VERSION 5.7 ;
  NOWIREEXTENSIONATPIN ON ;
  DIVIDERCHAR "/" ;
  BUSBITCHARS "[]" ;
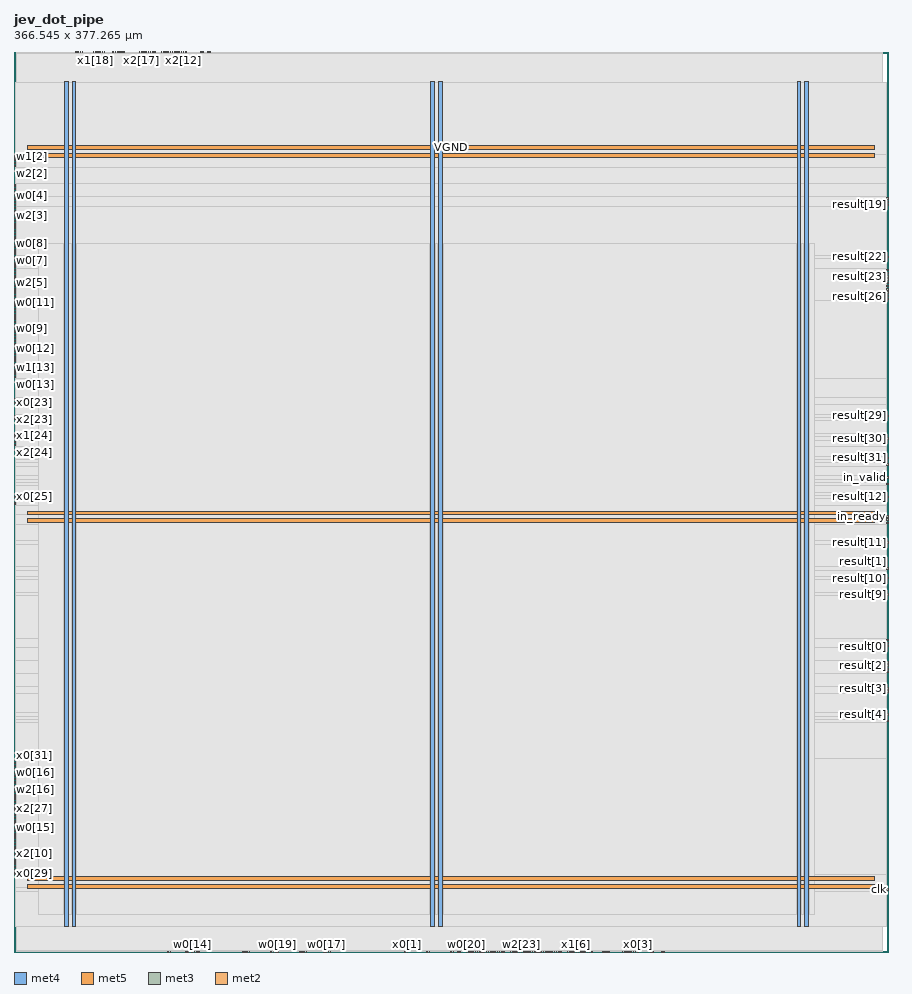
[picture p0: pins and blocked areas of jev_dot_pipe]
MACRO jev_dot_pipe
  CLASS BLOCK ;
  FOREIGN jev_dot_pipe ;
  ORIGIN 0.000 0.000 ;
  SIZE 366.545 BY 377.265 ;
  PIN VGND
    DIRECTION INOUT ;
    USE GROUND ;
    PORT
      LAYER met4 ;
        RECT 24.340 10.640 25.940 364.720 ;
    END
    PORT
      LAYER met4 ;
        RECT 177.940 10.640 179.540 364.720 ;
    END
    PORT
      LAYER met4 ;
        RECT 331.540 10.640 333.140 364.720 ;
    END
    PORT
      LAYER met5 ;
        RECT 5.520 30.030 360.640 31.630 ;
    END
    PORT
      LAYER met5 ;
        RECT 5.520 183.210 360.640 184.810 ;
    END
    PORT
      LAYER met5 ;
        RECT 5.520 336.390 360.640 337.990 ;
    END
  END VGND
  PIN VPWR
    DIRECTION INOUT ;
    USE POWER ;
    PORT
      LAYER met4 ;
        RECT 21.040 10.640 22.640 364.720 ;
    END
    PORT
      LAYER met4 ;
        RECT 174.640 10.640 176.240 364.720 ;
    END
    PORT
      LAYER met4 ;
        RECT 328.240 10.640 329.840 364.720 ;
    END
    PORT
      LAYER met5 ;
        RECT 5.520 26.730 360.640 28.330 ;
    END
    PORT
      LAYER met5 ;
        RECT 5.520 179.910 360.640 181.510 ;
    END
    PORT
      LAYER met5 ;
        RECT 5.520 333.090 360.640 334.690 ;
    END
  END VPWR
  PIN clk
    DIRECTION INPUT ;
    USE SIGNAL ;
    ANTENNAGATEAREA 0.852000 ;
    PORT
      LAYER met3 ;
        RECT 365.945 25.880 366.545 26.480 ;
    END
  END clk
  PIN in_ready
    DIRECTION OUTPUT ;
    USE SIGNAL ;
    ANTENNADIFFAREA 0.383400 ;
    PORT
      LAYER met3 ;
        RECT 365.945 182.280 366.545 182.880 ;
    END
  END in_ready
  PIN in_valid
    DIRECTION INPUT ;
    USE SIGNAL ;
    ANTENNAGATEAREA 0.196500 ;
    PORT
      LAYER met3 ;
        RECT 365.945 198.600 366.545 199.200 ;
    END
  END in_valid
  PIN out_ready
    DIRECTION INPUT ;
    USE SIGNAL ;
    ANTENNAGATEAREA 0.196500 ;
    PORT
      LAYER met3 ;
        RECT 365.945 180.920 366.545 181.520 ;
    END
  END out_ready
  PIN out_valid
    DIRECTION OUTPUT ;
    USE SIGNAL ;
    ANTENNADIFFAREA 0.383400 ;
    PORT
      LAYER met3 ;
        RECT 365.945 179.560 366.545 180.160 ;
    END
  END out_valid
  PIN result[0]
    DIRECTION OUTPUT ;
    USE SIGNAL ;
    ANTENNADIFFAREA 0.383400 ;
    PORT
      LAYER met3 ;
        RECT 365.945 127.880 366.545 128.480 ;
    END
  END result[0]
  PIN result[10]
    DIRECTION OUTPUT ;
    USE SIGNAL ;
    ANTENNADIFFAREA 0.383400 ;
    PORT
      LAYER met3 ;
        RECT 365.945 156.440 366.545 157.040 ;
    END
  END result[10]
  PIN result[11]
    DIRECTION OUTPUT ;
    USE SIGNAL ;
    ANTENNADIFFAREA 0.383400 ;
    PORT
      LAYER met3 ;
        RECT 365.945 171.400 366.545 172.000 ;
    END
  END result[11]
  PIN result[12]
    DIRECTION OUTPUT ;
    USE SIGNAL ;
    ANTENNADIFFAREA 0.383400 ;
    PORT
      LAYER met3 ;
        RECT 365.945 190.440 366.545 191.040 ;
    END
  END result[12]
  PIN result[13]
    DIRECTION OUTPUT ;
    USE SIGNAL ;
    ANTENNADIFFAREA 0.383400 ;
    PORT
      LAYER met3 ;
        RECT 365.945 195.880 366.545 196.480 ;
    END
  END result[13]
  PIN result[14]
    DIRECTION OUTPUT ;
    USE SIGNAL ;
    ANTENNADIFFAREA 0.383400 ;
    PORT
      LAYER met3 ;
        RECT 365.945 281.560 366.545 282.160 ;
    END
  END result[14]
  PIN result[15]
    DIRECTION OUTPUT ;
    USE SIGNAL ;
    ANTENNADIFFAREA 0.383400 ;
    PORT
      LAYER met3 ;
        RECT 365.945 280.200 366.545 280.800 ;
    END
  END result[15]
  PIN result[16]
    DIRECTION OUTPUT ;
    USE SIGNAL ;
    ANTENNADIFFAREA 0.383400 ;
    PORT
      LAYER met3 ;
        RECT 365.945 274.760 366.545 275.360 ;
    END
  END result[16]
  PIN result[17]
    DIRECTION OUTPUT ;
    USE SIGNAL ;
    ANTENNADIFFAREA 0.383400 ;
    PORT
      LAYER met3 ;
        RECT 365.945 285.640 366.545 286.240 ;
    END
  END result[17]
  PIN result[18]
    DIRECTION OUTPUT ;
    USE SIGNAL ;
    ANTENNADIFFAREA 0.383400 ;
    PORT
      LAYER met3 ;
        RECT 365.945 284.280 366.545 284.880 ;
    END
  END result[18]
  PIN result[19]
    DIRECTION OUTPUT ;
    USE SIGNAL ;
    ANTENNADIFFAREA 0.383400 ;
    PORT
      LAYER met3 ;
        RECT 365.945 312.840 366.545 313.440 ;
    END
  END result[19]
  PIN result[1]
    DIRECTION OUTPUT ;
    USE SIGNAL ;
    ANTENNADIFFAREA 0.383400 ;
    PORT
      LAYER met3 ;
        RECT 365.945 160.520 366.545 161.120 ;
    END
  END result[1]
  PIN result[20]
    DIRECTION OUTPUT ;
    USE SIGNAL ;
    ANTENNADIFFAREA 0.383400 ;
    PORT
      LAYER met3 ;
        RECT 365.945 314.200 366.545 314.800 ;
    END
  END result[20]
  PIN result[21]
    DIRECTION OUTPUT ;
    USE SIGNAL ;
    ANTENNADIFFAREA 0.383400 ;
    PORT
      LAYER met3 ;
        RECT 365.945 315.560 366.545 316.160 ;
    END
  END result[21]
  PIN result[22]
    DIRECTION OUTPUT ;
    USE SIGNAL ;
    ANTENNADIFFAREA 0.383400 ;
    PORT
      LAYER met3 ;
        RECT 365.945 291.080 366.545 291.680 ;
    END
  END result[22]
  PIN result[23]
    DIRECTION OUTPUT ;
    USE SIGNAL ;
    ANTENNADIFFAREA 0.383400 ;
    PORT
      LAYER met3 ;
        RECT 365.945 282.920 366.545 283.520 ;
    END
  END result[23]
  PIN result[24]
    DIRECTION OUTPUT ;
    USE SIGNAL ;
    ANTENNADIFFAREA 0.383400 ;
    PORT
      LAYER met3 ;
        RECT 365.945 276.120 366.545 276.720 ;
    END
  END result[24]
  PIN result[25]
    DIRECTION OUTPUT ;
    USE SIGNAL ;
    ANTENNADIFFAREA 0.383400 ;
    PORT
      LAYER met3 ;
        RECT 365.945 278.840 366.545 279.440 ;
    END
  END result[25]
  PIN result[26]
    DIRECTION OUTPUT ;
    USE SIGNAL ;
    ANTENNADIFFAREA 0.383400 ;
    PORT
      LAYER met3 ;
        RECT 365.945 277.480 366.545 278.080 ;
    END
  END result[26]
  PIN result[27]
    DIRECTION OUTPUT ;
    USE SIGNAL ;
    ANTENNADIFFAREA 0.383400 ;
    PORT
      LAYER met3 ;
        RECT 365.945 273.400 366.545 274.000 ;
    END
  END result[27]
  PIN result[28]
    DIRECTION OUTPUT ;
    USE SIGNAL ;
    ANTENNADIFFAREA 0.383400 ;
    PORT
      LAYER met3 ;
        RECT 365.945 206.760 366.545 207.360 ;
    END
  END result[28]
  PIN result[29]
    DIRECTION OUTPUT ;
    USE SIGNAL ;
    ANTENNADIFFAREA 0.383400 ;
    PORT
      LAYER met3 ;
        RECT 365.945 224.440 366.545 225.040 ;
    END
  END result[29]
  PIN result[2]
    DIRECTION OUTPUT ;
    USE SIGNAL ;
    ANTENNADIFFAREA 0.383400 ;
    PORT
      LAYER met3 ;
        RECT 365.945 119.720 366.545 120.320 ;
    END
  END result[2]
  PIN result[30]
    DIRECTION OUTPUT ;
    USE SIGNAL ;
    ANTENNADIFFAREA 0.383400 ;
    PORT
      LAYER met3 ;
        RECT 365.945 214.920 366.545 215.520 ;
    END
  END result[30]
  PIN result[31]
    DIRECTION OUTPUT ;
    USE SIGNAL ;
    ANTENNADIFFAREA 0.383400 ;
    PORT
      LAYER met3 ;
        RECT 365.945 204.040 366.545 204.640 ;
    END
  END result[31]
  PIN result[3]
    DIRECTION OUTPUT ;
    USE SIGNAL ;
    ANTENNADIFFAREA 0.383400 ;
    PORT
      LAYER met3 ;
        RECT 365.945 110.200 366.545 110.800 ;
    END
  END result[3]
  PIN result[4]
    DIRECTION OUTPUT ;
    USE SIGNAL ;
    ANTENNADIFFAREA 0.383400 ;
    PORT
      LAYER met3 ;
        RECT 365.945 99.320 366.545 99.920 ;
    END
  END result[4]
  PIN result[5]
    DIRECTION OUTPUT ;
    USE SIGNAL ;
    ANTENNADIFFAREA 0.383400 ;
    PORT
      LAYER met3 ;
        RECT 365.945 96.600 366.545 97.200 ;
    END
  END result[5]
  PIN result[6]
    DIRECTION OUTPUT ;
    USE SIGNAL ;
    ANTENNADIFFAREA 0.383400 ;
    PORT
      LAYER met3 ;
        RECT 365.945 108.840 366.545 109.440 ;
    END
  END result[6]
  PIN result[7]
    DIRECTION OUTPUT ;
    USE SIGNAL ;
    ANTENNADIFFAREA 0.383400 ;
    PORT
      LAYER met3 ;
        RECT 365.945 121.080 366.545 121.680 ;
    END
  END result[7]
  PIN result[8]
    DIRECTION OUTPUT ;
    USE SIGNAL ;
    ANTENNADIFFAREA 0.383400 ;
    PORT
      LAYER met3 ;
        RECT 365.945 130.600 366.545 131.200 ;
    END
  END result[8]
  PIN result[9]
    DIRECTION OUTPUT ;
    USE SIGNAL ;
    ANTENNADIFFAREA 0.383400 ;
    PORT
      LAYER met3 ;
        RECT 365.945 149.640 366.545 150.240 ;
    END
  END result[9]
  PIN rst
    DIRECTION INPUT ;
    USE SIGNAL ;
    ANTENNAGATEAREA 0.213000 ;
    PORT
      LAYER met3 ;
        RECT 365.945 129.240 366.545 129.840 ;
    END
  END rst
  PIN w0[0]
    DIRECTION INPUT ;
    USE SIGNAL ;
    ANTENNAGATEAREA 0.196500 ;
    PORT
      LAYER met2 ;
        RECT 37.810 376.985 38.090 377.265 ;
    END
  END w0[0]
  PIN w0[10]
    DIRECTION INPUT ;
    USE SIGNAL ;
    ANTENNAGATEAREA 0.196500 ;
    PORT
      LAYER met3 ;
        RECT 0.000 281.560 0.600 282.160 ;
    END
  END w0[10]
  PIN w0[11]
    DIRECTION INPUT ;
    USE SIGNAL ;
    ANTENNAGATEAREA 0.196500 ;
    PORT
      LAYER met3 ;
        RECT 0.000 272.040 0.600 272.640 ;
    END
  END w0[11]
  PIN w0[12]
    DIRECTION INPUT ;
    USE SIGNAL ;
    ANTENNAGATEAREA 0.196500 ;
    PORT
      LAYER met3 ;
        RECT 0.000 255.720 0.600 256.320 ;
    END
  END w0[12]
  PIN w0[13]
    DIRECTION INPUT ;
    USE SIGNAL ;
    ANTENNAGATEAREA 0.196500 ;
    PORT
      LAYER met3 ;
        RECT 0.000 240.760 0.600 241.360 ;
    END
  END w0[13]
  PIN w0[14]
    DIRECTION INPUT ;
    USE SIGNAL ;
    ANTENNAGATEAREA 0.196500 ;
    PORT
      LAYER met2 ;
        RECT 74.610 0.000 74.890 0.280 ;
    END
  END w0[14]
  PIN w0[15]
    DIRECTION INPUT ;
    USE SIGNAL ;
    ANTENNAGATEAREA 0.196500 ;
    PORT
      LAYER met3 ;
        RECT 0.000 51.720 0.600 52.320 ;
    END
  END w0[15]
  PIN w0[16]
    DIRECTION INPUT ;
    USE SIGNAL ;
    ANTENNAGATEAREA 0.196500 ;
    PORT
      LAYER met3 ;
        RECT 0.000 74.840 0.600 75.440 ;
    END
  END w0[16]
  PIN w0[17]
    DIRECTION INPUT ;
    USE SIGNAL ;
    ANTENNAGATEAREA 0.196500 ;
    PORT
      LAYER met2 ;
        RECT 130.730 0.000 131.010 0.280 ;
    END
  END w0[17]
  PIN w0[18]
    DIRECTION INPUT ;
    USE SIGNAL ;
    ANTENNAGATEAREA 0.196500 ;
    PORT
      LAYER met2 ;
        RECT 122.450 0.000 122.730 0.280 ;
    END
  END w0[18]
  PIN w0[19]
    DIRECTION INPUT ;
    USE SIGNAL ;
    ANTENNAGATEAREA 0.196500 ;
    PORT
      LAYER met2 ;
        RECT 110.490 0.000 110.770 0.280 ;
    END
  END w0[19]
  PIN w0[1]
    DIRECTION INPUT ;
    USE SIGNAL ;
    ANTENNAGATEAREA 0.196500 ;
    PORT
      LAYER met2 ;
        RECT 26.770 376.985 27.050 377.265 ;
    END
  END w0[1]
  PIN w0[20]
    DIRECTION INPUT ;
    USE SIGNAL ;
    ANTENNAGATEAREA 0.196500 ;
    PORT
      LAYER met2 ;
        RECT 189.610 0.000 189.890 0.280 ;
    END
  END w0[20]
  PIN w0[21]
    DIRECTION INPUT ;
    USE SIGNAL ;
    ANTENNAGATEAREA 0.196500 ;
    PORT
      LAYER met2 ;
        RECT 201.570 0.000 201.850 0.280 ;
    END
  END w0[21]
  PIN w0[22]
    DIRECTION INPUT ;
    USE SIGNAL ;
    ANTENNAGATEAREA 0.196500 ;
    PORT
      LAYER met3 ;
        RECT 365.945 117.000 366.545 117.600 ;
    END
  END w0[22]
  PIN w0[23]
    DIRECTION INPUT ;
    USE SIGNAL ;
    ANTENNAGATEAREA 0.196500 ;
    PORT
      LAYER met2 ;
        RECT 218.130 0.000 218.410 0.280 ;
    END
  END w0[23]
  PIN w0[24]
    DIRECTION INPUT ;
    USE SIGNAL ;
    ANTENNAGATEAREA 0.196500 ;
    PORT
      LAYER met2 ;
        RECT 208.010 0.000 208.290 0.280 ;
    END
  END w0[24]
  PIN w0[25]
    DIRECTION INPUT ;
    USE SIGNAL ;
    ANTENNAGATEAREA 0.196500 ;
    PORT
      LAYER met2 ;
        RECT 225.490 0.000 225.770 0.280 ;
    END
  END w0[25]
  PIN w0[26]
    DIRECTION INPUT ;
    USE SIGNAL ;
    ANTENNAGATEAREA 0.196500 ;
    PORT
      LAYER met2 ;
        RECT 229.170 0.000 229.450 0.280 ;
    END
  END w0[26]
  PIN w0[27]
    DIRECTION INPUT ;
    USE SIGNAL ;
    ANTENNAGATEAREA 0.196500 ;
    PORT
      LAYER met2 ;
        RECT 242.050 0.000 242.330 0.280 ;
    END
  END w0[27]
  PIN w0[28]
    DIRECTION INPUT ;
    USE SIGNAL ;
    ANTENNAGATEAREA 0.196500 ;
    PORT
      LAYER met2 ;
        RECT 234.690 0.000 234.970 0.280 ;
    END
  END w0[28]
  PIN w0[29]
    DIRECTION INPUT ;
    USE SIGNAL ;
    ANTENNAGATEAREA 0.196500 ;
    PORT
      LAYER met2 ;
        RECT 216.290 0.000 216.570 0.280 ;
    END
  END w0[29]
  PIN w0[2]
    DIRECTION INPUT ;
    USE SIGNAL ;
    ANTENNAGATEAREA 0.196500 ;
    PORT
      LAYER met3 ;
        RECT 0.000 331.880 0.600 332.480 ;
    END
  END w0[2]
  PIN w0[30]
    DIRECTION INPUT ;
    USE SIGNAL ;
    ANTENNAGATEAREA 0.196500 ;
    PORT
      LAYER met2 ;
        RECT 196.050 0.000 196.330 0.280 ;
    END
  END w0[30]
  PIN w0[31]
    DIRECTION INPUT ;
    USE SIGNAL ;
    ANTENNAGATEAREA 0.196500 ;
    PORT
      LAYER met2 ;
        RECT 223.650 0.000 223.930 0.280 ;
    END
  END w0[31]
  PIN w0[3]
    DIRECTION INPUT ;
    USE SIGNAL ;
    ANTENNAGATEAREA 0.196500 ;
    PORT
      LAYER met3 ;
        RECT 0.000 315.560 0.600 316.160 ;
    END
  END w0[3]
  PIN w0[4]
    DIRECTION INPUT ;
    USE SIGNAL ;
    ANTENNAGATEAREA 0.196500 ;
    PORT
      LAYER met3 ;
        RECT 0.000 316.920 0.600 317.520 ;
    END
  END w0[4]
  PIN w0[5]
    DIRECTION INPUT ;
    USE SIGNAL ;
    ANTENNAGATEAREA 0.196500 ;
    PORT
      LAYER met3 ;
        RECT 0.000 273.400 0.600 274.000 ;
    END
  END w0[5]
  PIN w0[6]
    DIRECTION INPUT ;
    USE SIGNAL ;
    ANTENNAGATEAREA 0.196500 ;
    PORT
      LAYER met3 ;
        RECT 0.000 267.960 0.600 268.560 ;
    END
  END w0[6]
  PIN w0[7]
    DIRECTION INPUT ;
    USE SIGNAL ;
    ANTENNAGATEAREA 0.196500 ;
    PORT
      LAYER met3 ;
        RECT 0.000 289.720 0.600 290.320 ;
    END
  END w0[7]
  PIN w0[8]
    DIRECTION INPUT ;
    USE SIGNAL ;
    ANTENNAGATEAREA 0.196500 ;
    PORT
      LAYER met3 ;
        RECT 0.000 293.800 0.600 294.400 ;
    END
  END w0[8]
  PIN w0[9]
    DIRECTION INPUT ;
    USE SIGNAL ;
    ANTENNAGATEAREA 0.196500 ;
    PORT
      LAYER met3 ;
        RECT 0.000 261.160 0.600 261.760 ;
    END
  END w0[9]
  PIN w1[0]
    DIRECTION INPUT ;
    USE SIGNAL ;
    ANTENNAGATEAREA 0.196500 ;
    PORT
      LAYER met2 ;
        RECT 36.890 376.985 37.170 377.265 ;
    END
  END w1[0]
  PIN w1[10]
    DIRECTION INPUT ;
    USE SIGNAL ;
    ANTENNAGATEAREA 0.196500 ;
    PORT
      LAYER met3 ;
        RECT 0.000 285.640 0.600 286.240 ;
    END
  END w1[10]
  PIN w1[11]
    DIRECTION INPUT ;
    USE SIGNAL ;
    ANTENNAGATEAREA 0.196500 ;
    PORT
      LAYER met3 ;
        RECT 0.000 274.760 0.600 275.360 ;
    END
  END w1[11]
  PIN w1[12]
    DIRECTION INPUT ;
    USE SIGNAL ;
    ANTENNAGATEAREA 0.196500 ;
    PORT
      LAYER met3 ;
        RECT 0.000 254.360 0.600 254.960 ;
    END
  END w1[12]
  PIN w1[13]
    DIRECTION INPUT ;
    USE SIGNAL ;
    ANTENNAGATEAREA 0.196500 ;
    PORT
      LAYER met3 ;
        RECT 0.000 244.840 0.600 245.440 ;
    END
  END w1[13]
  PIN w1[14]
    DIRECTION INPUT ;
    USE SIGNAL ;
    ANTENNAGATEAREA 0.196500 ;
    PORT
      LAYER met2 ;
        RECT 75.530 0.000 75.810 0.280 ;
    END
  END w1[14]
  PIN w1[15]
    DIRECTION INPUT ;
    USE SIGNAL ;
    ANTENNAGATEAREA 0.196500 ;
    PORT
      LAYER met3 ;
        RECT 0.000 53.080 0.600 53.680 ;
    END
  END w1[15]
  PIN w1[16]
    DIRECTION INPUT ;
    USE SIGNAL ;
    ANTENNAGATEAREA 0.196500 ;
    PORT
      LAYER met3 ;
        RECT 0.000 72.120 0.600 72.720 ;
    END
  END w1[16]
  PIN w1[17]
    DIRECTION INPUT ;
    USE SIGNAL ;
    ANTENNAGATEAREA 0.196500 ;
    PORT
      LAYER met2 ;
        RECT 129.810 0.000 130.090 0.280 ;
    END
  END w1[17]
  PIN w1[18]
    DIRECTION INPUT ;
    USE SIGNAL ;
    ANTENNAGATEAREA 0.196500 ;
    PORT
      LAYER met2 ;
        RECT 121.530 0.000 121.810 0.280 ;
    END
  END w1[18]
  PIN w1[19]
    DIRECTION INPUT ;
    USE SIGNAL ;
    ANTENNAGATEAREA 0.196500 ;
    PORT
      LAYER met2 ;
        RECT 109.570 0.000 109.850 0.280 ;
    END
  END w1[19]
  PIN w1[1]
    DIRECTION INPUT ;
    USE SIGNAL ;
    ANTENNAGATEAREA 0.196500 ;
    PORT
      LAYER met2 ;
        RECT 25.850 376.985 26.130 377.265 ;
    END
  END w1[1]
  PIN w1[20]
    DIRECTION INPUT ;
    USE SIGNAL ;
    ANTENNAGATEAREA 0.196500 ;
    PORT
      LAYER met2 ;
        RECT 190.530 0.000 190.810 0.280 ;
    END
  END w1[20]
  PIN w1[21]
    DIRECTION INPUT ;
    USE SIGNAL ;
    ANTENNAGATEAREA 0.196500 ;
    PORT
      LAYER met2 ;
        RECT 200.650 0.000 200.930 0.280 ;
    END
  END w1[21]
  PIN w1[22]
    DIRECTION INPUT ;
    USE SIGNAL ;
    ANTENNAGATEAREA 0.196500 ;
    PORT
      LAYER met3 ;
        RECT 365.945 118.360 366.545 118.960 ;
    END
  END w1[22]
  PIN w1[23]
    DIRECTION INPUT ;
    USE SIGNAL ;
    ANTENNAGATEAREA 0.196500 ;
    PORT
      LAYER met2 ;
        RECT 217.210 0.000 217.490 0.280 ;
    END
  END w1[23]
  PIN w1[24]
    DIRECTION INPUT ;
    USE SIGNAL ;
    ANTENNAGATEAREA 0.196500 ;
    PORT
      LAYER met2 ;
        RECT 210.770 0.000 211.050 0.280 ;
    END
  END w1[24]
  PIN w1[25]
    DIRECTION INPUT ;
    USE SIGNAL ;
    ANTENNAGATEAREA 0.196500 ;
    PORT
      LAYER met2 ;
        RECT 224.570 0.000 224.850 0.280 ;
    END
  END w1[25]
  PIN w1[26]
    DIRECTION INPUT ;
    USE SIGNAL ;
    ANTENNAGATEAREA 0.196500 ;
    PORT
      LAYER met2 ;
        RECT 228.250 0.000 228.530 0.280 ;
    END
  END w1[26]
  PIN w1[27]
    DIRECTION INPUT ;
    USE SIGNAL ;
    ANTENNAGATEAREA 0.196500 ;
    PORT
      LAYER met2 ;
        RECT 241.130 0.000 241.410 0.280 ;
    END
  END w1[27]
  PIN w1[28]
    DIRECTION INPUT ;
    USE SIGNAL ;
    ANTENNAGATEAREA 0.196500 ;
    PORT
      LAYER met2 ;
        RECT 233.770 0.000 234.050 0.280 ;
    END
  END w1[28]
  PIN w1[29]
    DIRECTION INPUT ;
    USE SIGNAL ;
    ANTENNAGATEAREA 0.196500 ;
    PORT
      LAYER met2 ;
        RECT 214.450 0.000 214.730 0.280 ;
    END
  END w1[29]
  PIN w1[2]
    DIRECTION INPUT ;
    USE SIGNAL ;
    ANTENNAGATEAREA 0.196500 ;
    PORT
      LAYER met3 ;
        RECT 0.000 333.240 0.600 333.840 ;
    END
  END w1[2]
  PIN w1[30]
    DIRECTION INPUT ;
    USE SIGNAL ;
    ANTENNAGATEAREA 0.196500 ;
    PORT
      LAYER met2 ;
        RECT 195.130 0.000 195.410 0.280 ;
    END
  END w1[30]
  PIN w1[31]
    DIRECTION INPUT ;
    USE SIGNAL ;
    ANTENNAGATEAREA 0.196500 ;
    PORT
      LAYER met2 ;
        RECT 219.050 0.000 219.330 0.280 ;
    END
  END w1[31]
  PIN w1[3]
    DIRECTION INPUT ;
    USE SIGNAL ;
    ANTENNAGATEAREA 0.196500 ;
    PORT
      LAYER met3 ;
        RECT 0.000 312.840 0.600 313.440 ;
    END
  END w1[3]
  PIN w1[4]
    DIRECTION INPUT ;
    USE SIGNAL ;
    ANTENNAGATEAREA 0.196500 ;
    PORT
      LAYER met3 ;
        RECT 0.000 318.280 0.600 318.880 ;
    END
  END w1[4]
  PIN w1[5]
    DIRECTION INPUT ;
    USE SIGNAL ;
    ANTENNAGATEAREA 0.196500 ;
    PORT
      LAYER met3 ;
        RECT 0.000 276.120 0.600 276.720 ;
    END
  END w1[5]
  PIN w1[6]
    DIRECTION INPUT ;
    USE SIGNAL ;
    ANTENNAGATEAREA 0.196500 ;
    PORT
      LAYER met3 ;
        RECT 0.000 269.320 0.600 269.920 ;
    END
  END w1[6]
  PIN w1[7]
    DIRECTION INPUT ;
    USE SIGNAL ;
    ANTENNAGATEAREA 0.196500 ;
    PORT
      LAYER met3 ;
        RECT 0.000 292.440 0.600 293.040 ;
    END
  END w1[7]
  PIN w1[8]
    DIRECTION INPUT ;
    USE SIGNAL ;
    ANTENNAGATEAREA 0.196500 ;
    PORT
      LAYER met3 ;
        RECT 0.000 291.080 0.600 291.680 ;
    END
  END w1[8]
  PIN w1[9]
    DIRECTION INPUT ;
    USE SIGNAL ;
    ANTENNAGATEAREA 0.196500 ;
    PORT
      LAYER met3 ;
        RECT 0.000 262.520 0.600 263.120 ;
    END
  END w1[9]
  PIN w2[0]
    DIRECTION INPUT ;
    USE SIGNAL ;
    ANTENNAGATEAREA 0.196500 ;
    PORT
      LAYER met2 ;
        RECT 41.490 376.985 41.770 377.265 ;
    END
  END w2[0]
  PIN w2[10]
    DIRECTION INPUT ;
    USE SIGNAL ;
    ANTENNAGATEAREA 0.196500 ;
    PORT
      LAYER met3 ;
        RECT 0.000 270.680 0.600 271.280 ;
    END
  END w2[10]
  PIN w2[11]
    DIRECTION INPUT ;
    USE SIGNAL ;
    ANTENNAGATEAREA 0.196500 ;
    PORT
      LAYER met3 ;
        RECT 0.000 259.800 0.600 260.400 ;
    END
  END w2[11]
  PIN w2[12]
    DIRECTION INPUT ;
    USE SIGNAL ;
    ANTENNAGATEAREA 0.196500 ;
    PORT
      LAYER met3 ;
        RECT 0.000 251.640 0.600 252.240 ;
    END
  END w2[12]
  PIN w2[13]
    DIRECTION INPUT ;
    USE SIGNAL ;
    ANTENNAGATEAREA 0.196500 ;
    PORT
      LAYER met3 ;
        RECT 0.000 242.120 0.600 242.720 ;
    END
  END w2[13]
  PIN w2[14]
    DIRECTION INPUT ;
    USE SIGNAL ;
    ANTENNAGATEAREA 0.196500 ;
    PORT
      LAYER met3 ;
        RECT 0.000 63.960 0.600 64.560 ;
    END
  END w2[14]
  PIN w2[15]
    DIRECTION INPUT ;
    USE SIGNAL ;
    ANTENNAGATEAREA 0.196500 ;
    PORT
      LAYER met3 ;
        RECT 0.000 62.600 0.600 63.200 ;
    END
  END w2[15]
  PIN w2[16]
    DIRECTION INPUT ;
    USE SIGNAL ;
    ANTENNAGATEAREA 0.196500 ;
    PORT
      LAYER met3 ;
        RECT 0.000 70.760 0.600 71.360 ;
    END
  END w2[16]
  PIN w2[17]
    DIRECTION INPUT ;
    USE SIGNAL ;
    ANTENNAGATEAREA 0.196500 ;
    PORT
      LAYER met2 ;
        RECT 132.570 0.000 132.850 0.280 ;
    END
  END w2[17]
  PIN w2[18]
    DIRECTION INPUT ;
    USE SIGNAL ;
    ANTENNAGATEAREA 0.196500 ;
    PORT
      LAYER met2 ;
        RECT 120.610 0.000 120.890 0.280 ;
    END
  END w2[18]
  PIN w2[19]
    DIRECTION INPUT ;
    USE SIGNAL ;
    ANTENNAGATEAREA 0.196500 ;
    PORT
      LAYER met2 ;
        RECT 108.650 0.000 108.930 0.280 ;
    END
  END w2[19]
  PIN w2[1]
    DIRECTION INPUT ;
    USE SIGNAL ;
    ANTENNAGATEAREA 0.196500 ;
    PORT
      LAYER met2 ;
        RECT 28.610 376.985 28.890 377.265 ;
    END
  END w2[1]
  PIN w2[20]
    DIRECTION INPUT ;
    USE SIGNAL ;
    ANTENNAGATEAREA 0.196500 ;
    PORT
      LAYER met2 ;
        RECT 192.370 0.000 192.650 0.280 ;
    END
  END w2[20]
  PIN w2[21]
    DIRECTION INPUT ;
    USE SIGNAL ;
    ANTENNAGATEAREA 0.196500 ;
    PORT
      LAYER met2 ;
        RECT 198.810 0.000 199.090 0.280 ;
    END
  END w2[21]
  PIN w2[22]
    DIRECTION INPUT ;
    USE SIGNAL ;
    ANTENNAGATEAREA 0.196500 ;
    PORT
      LAYER met2 ;
        RECT 197.890 0.000 198.170 0.280 ;
    END
  END w2[22]
  PIN w2[23]
    DIRECTION INPUT ;
    USE SIGNAL ;
    ANTENNAGATEAREA 0.196500 ;
    PORT
      LAYER met2 ;
        RECT 212.610 0.000 212.890 0.280 ;
    END
  END w2[23]
  PIN w2[24]
    DIRECTION INPUT ;
    USE SIGNAL ;
    ANTENNAGATEAREA 0.196500 ;
    PORT
      LAYER met2 ;
        RECT 209.850 0.000 210.130 0.280 ;
    END
  END w2[24]
  PIN w2[25]
    DIRECTION INPUT ;
    USE SIGNAL ;
    ANTENNAGATEAREA 0.196500 ;
    PORT
      LAYER met2 ;
        RECT 219.970 0.000 220.250 0.280 ;
    END
  END w2[25]
  PIN w2[26]
    DIRECTION INPUT ;
    USE SIGNAL ;
    ANTENNAGATEAREA 0.196500 ;
    PORT
      LAYER met2 ;
        RECT 227.330 0.000 227.610 0.280 ;
    END
  END w2[26]
  PIN w2[27]
    DIRECTION INPUT ;
    USE SIGNAL ;
    ANTENNAGATEAREA 0.196500 ;
    PORT
      LAYER met2 ;
        RECT 240.210 0.000 240.490 0.280 ;
    END
  END w2[27]
  PIN w2[28]
    DIRECTION INPUT ;
    USE SIGNAL ;
    ANTENNAGATEAREA 0.196500 ;
    PORT
      LAYER met2 ;
        RECT 232.850 0.000 233.130 0.280 ;
    END
  END w2[28]
  PIN w2[29]
    DIRECTION INPUT ;
    USE SIGNAL ;
    ANTENNAGATEAREA 0.196500 ;
    PORT
      LAYER met2 ;
        RECT 213.530 0.000 213.810 0.280 ;
    END
  END w2[29]
  PIN w2[2]
    DIRECTION INPUT ;
    USE SIGNAL ;
    ANTENNAGATEAREA 0.196500 ;
    PORT
      LAYER met3 ;
        RECT 0.000 329.160 0.600 329.760 ;
    END
  END w2[2]
  PIN w2[30]
    DIRECTION INPUT ;
    USE SIGNAL ;
    ANTENNAGATEAREA 0.196500 ;
    PORT
      LAYER met2 ;
        RECT 194.210 0.000 194.490 0.280 ;
    END
  END w2[30]
  PIN w2[31]
    DIRECTION INPUT ;
    USE SIGNAL ;
    ANTENNAGATEAREA 0.196500 ;
    PORT
      LAYER met2 ;
        RECT 220.890 0.000 221.170 0.280 ;
    END
  END w2[31]
  PIN w2[3]
    DIRECTION INPUT ;
    USE SIGNAL ;
    ANTENNAGATEAREA 0.196500 ;
    PORT
      LAYER met3 ;
        RECT 0.000 311.480 0.600 312.080 ;
    END
  END w2[3]
  PIN w2[4]
    DIRECTION INPUT ;
    USE SIGNAL ;
    ANTENNAGATEAREA 0.196500 ;
    PORT
      LAYER met3 ;
        RECT 0.000 321.000 0.600 321.600 ;
    END
  END w2[4]
  PIN w2[5]
    DIRECTION INPUT ;
    USE SIGNAL ;
    ANTENNAGATEAREA 0.196500 ;
    PORT
      LAYER met3 ;
        RECT 0.000 277.480 0.600 278.080 ;
    END
  END w2[5]
  PIN w2[6]
    DIRECTION INPUT ;
    USE SIGNAL ;
    ANTENNAGATEAREA 0.196500 ;
    PORT
      LAYER met3 ;
        RECT 0.000 257.080 0.600 257.680 ;
    END
  END w2[6]
  PIN w2[7]
    DIRECTION INPUT ;
    USE SIGNAL ;
    ANTENNAGATEAREA 0.196500 ;
    PORT
      LAYER met3 ;
        RECT 0.000 287.000 0.600 287.600 ;
    END
  END w2[7]
  PIN w2[8]
    DIRECTION INPUT ;
    USE SIGNAL ;
    ANTENNAGATEAREA 0.196500 ;
    PORT
      LAYER met3 ;
        RECT 0.000 284.280 0.600 284.880 ;
    END
  END w2[8]
  PIN w2[9]
    DIRECTION INPUT ;
    USE SIGNAL ;
    ANTENNAGATEAREA 0.196500 ;
    PORT
      LAYER met3 ;
        RECT 0.000 263.880 0.600 264.480 ;
    END
  END w2[9]
  PIN w3[0]
    DIRECTION INPUT ;
    USE SIGNAL ;
    ANTENNAGATEAREA 0.196500 ;
    PORT
      LAYER met2 ;
        RECT 42.410 376.985 42.690 377.265 ;
    END
  END w3[0]
  PIN w3[10]
    DIRECTION INPUT ;
    USE SIGNAL ;
    ANTENNAGATEAREA 0.196500 ;
    PORT
      LAYER met3 ;
        RECT 0.000 278.840 0.600 279.440 ;
    END
  END w3[10]
  PIN w3[11]
    DIRECTION INPUT ;
    USE SIGNAL ;
    ANTENNAGATEAREA 0.196500 ;
    PORT
      LAYER met3 ;
        RECT 0.000 266.600 0.600 267.200 ;
    END
  END w3[11]
  PIN w3[12]
    DIRECTION INPUT ;
    USE SIGNAL ;
    ANTENNAGATEAREA 0.196500 ;
    PORT
      LAYER met3 ;
        RECT 0.000 253.000 0.600 253.600 ;
    END
  END w3[12]
  PIN w3[13]
    DIRECTION INPUT ;
    USE SIGNAL ;
    ANTENNAGATEAREA 0.196500 ;
    PORT
      LAYER met3 ;
        RECT 0.000 243.480 0.600 244.080 ;
    END
  END w3[13]
  PIN w3[14]
    DIRECTION INPUT ;
    USE SIGNAL ;
    ANTENNAGATEAREA 0.196500 ;
    PORT
      LAYER met3 ;
        RECT 0.000 54.440 0.600 55.040 ;
    END
  END w3[14]
  PIN w3[15]
    DIRECTION INPUT ;
    USE SIGNAL ;
    ANTENNAGATEAREA 0.196500 ;
    PORT
      LAYER met3 ;
        RECT 0.000 61.240 0.600 61.840 ;
    END
  END w3[15]
  PIN w3[16]
    DIRECTION INPUT ;
    USE SIGNAL ;
    ANTENNAGATEAREA 0.196500 ;
    PORT
      LAYER met3 ;
        RECT 0.000 73.480 0.600 74.080 ;
    END
  END w3[16]
  PIN w3[17]
    DIRECTION INPUT ;
    USE SIGNAL ;
    ANTENNAGATEAREA 0.196500 ;
    PORT
      LAYER met2 ;
        RECT 131.650 0.000 131.930 0.280 ;
    END
  END w3[17]
  PIN w3[18]
    DIRECTION INPUT ;
    USE SIGNAL ;
    ANTENNAGATEAREA 0.196500 ;
    PORT
      LAYER met2 ;
        RECT 119.690 0.000 119.970 0.280 ;
    END
  END w3[18]
  PIN w3[19]
    DIRECTION INPUT ;
    USE SIGNAL ;
    ANTENNAGATEAREA 0.196500 ;
    PORT
      LAYER met2 ;
        RECT 107.730 0.000 108.010 0.280 ;
    END
  END w3[19]
  PIN w3[1]
    DIRECTION INPUT ;
    USE SIGNAL ;
    ANTENNAGATEAREA 0.196500 ;
    PORT
      LAYER met2 ;
        RECT 27.690 376.985 27.970 377.265 ;
    END
  END w3[1]
  PIN w3[20]
    DIRECTION INPUT ;
    USE SIGNAL ;
    ANTENNAGATEAREA 0.196500 ;
    PORT
      LAYER met2 ;
        RECT 191.450 0.000 191.730 0.280 ;
    END
  END w3[20]
  PIN w3[21]
    DIRECTION INPUT ;
    USE SIGNAL ;
    ANTENNAGATEAREA 0.196500 ;
    PORT
      LAYER met2 ;
        RECT 199.730 0.000 200.010 0.280 ;
    END
  END w3[21]
  PIN w3[22]
    DIRECTION INPUT ;
    USE SIGNAL ;
    ANTENNAGATEAREA 0.196500 ;
    PORT
      LAYER met2 ;
        RECT 196.970 0.000 197.250 0.280 ;
    END
  END w3[22]
  PIN w3[23]
    DIRECTION INPUT ;
    USE SIGNAL ;
    ANTENNAGATEAREA 0.196500 ;
    PORT
      LAYER met2 ;
        RECT 211.690 0.000 211.970 0.280 ;
    END
  END w3[23]
  PIN w3[24]
    DIRECTION INPUT ;
    USE SIGNAL ;
    ANTENNAGATEAREA 0.196500 ;
    PORT
      LAYER met2 ;
        RECT 208.930 0.000 209.210 0.280 ;
    END
  END w3[24]
  PIN w3[25]
    DIRECTION INPUT ;
    USE SIGNAL ;
    ANTENNAGATEAREA 0.196500 ;
    PORT
      LAYER met2 ;
        RECT 221.810 0.000 222.090 0.280 ;
    END
  END w3[25]
  PIN w3[26]
    DIRECTION INPUT ;
    USE SIGNAL ;
    ANTENNAGATEAREA 0.196500 ;
    PORT
      LAYER met2 ;
        RECT 226.410 0.000 226.690 0.280 ;
    END
  END w3[26]
  PIN w3[27]
    DIRECTION INPUT ;
    USE SIGNAL ;
    ANTENNAGATEAREA 0.196500 ;
    PORT
      LAYER met2 ;
        RECT 239.290 0.000 239.570 0.280 ;
    END
  END w3[27]
  PIN w3[28]
    DIRECTION INPUT ;
    USE SIGNAL ;
    ANTENNAGATEAREA 0.196500 ;
    PORT
      LAYER met2 ;
        RECT 231.930 0.000 232.210 0.280 ;
    END
  END w3[28]
  PIN w3[29]
    DIRECTION INPUT ;
    USE SIGNAL ;
    ANTENNAGATEAREA 0.196500 ;
    PORT
      LAYER met2 ;
        RECT 215.370 0.000 215.650 0.280 ;
    END
  END w3[29]
  PIN w3[2]
    DIRECTION INPUT ;
    USE SIGNAL ;
    ANTENNAGATEAREA 0.196500 ;
    PORT
      LAYER met3 ;
        RECT 0.000 330.520 0.600 331.120 ;
    END
  END w3[2]
  PIN w3[30]
    DIRECTION INPUT ;
    USE SIGNAL ;
    ANTENNAGATEAREA 0.196500 ;
    PORT
      LAYER met2 ;
        RECT 193.290 0.000 193.570 0.280 ;
    END
  END w3[30]
  PIN w3[31]
    DIRECTION INPUT ;
    USE SIGNAL ;
    ANTENNAGATEAREA 0.196500 ;
    PORT
      LAYER met2 ;
        RECT 222.730 0.000 223.010 0.280 ;
    END
  END w3[31]
  PIN w3[3]
    DIRECTION INPUT ;
    USE SIGNAL ;
    ANTENNAGATEAREA 0.196500 ;
    PORT
      LAYER met3 ;
        RECT 0.000 310.120 0.600 310.720 ;
    END
  END w3[3]
  PIN w3[4]
    DIRECTION INPUT ;
    USE SIGNAL ;
    ANTENNAGATEAREA 0.196500 ;
    PORT
      LAYER met3 ;
        RECT 0.000 319.640 0.600 320.240 ;
    END
  END w3[4]
  PIN w3[5]
    DIRECTION INPUT ;
    USE SIGNAL ;
    ANTENNAGATEAREA 0.196500 ;
    PORT
      LAYER met3 ;
        RECT 0.000 280.200 0.600 280.800 ;
    END
  END w3[5]
  PIN w3[6]
    DIRECTION INPUT ;
    USE SIGNAL ;
    ANTENNAGATEAREA 0.196500 ;
    PORT
      LAYER met3 ;
        RECT 0.000 258.440 0.600 259.040 ;
    END
  END w3[6]
  PIN w3[7]
    DIRECTION INPUT ;
    USE SIGNAL ;
    ANTENNAGATEAREA 0.196500 ;
    PORT
      LAYER met3 ;
        RECT 0.000 282.920 0.600 283.520 ;
    END
  END w3[7]
  PIN w3[8]
    DIRECTION INPUT ;
    USE SIGNAL ;
    ANTENNAGATEAREA 0.196500 ;
    PORT
      LAYER met3 ;
        RECT 0.000 288.360 0.600 288.960 ;
    END
  END w3[8]
  PIN w3[9]
    DIRECTION INPUT ;
    USE SIGNAL ;
    ANTENNAGATEAREA 0.196500 ;
    PORT
      LAYER met3 ;
        RECT 0.000 265.240 0.600 265.840 ;
    END
  END w3[9]
  PIN x0[0]
    DIRECTION INPUT ;
    USE SIGNAL ;
    ANTENNAGATEAREA 0.196500 ;
    PORT
      LAYER met2 ;
        RECT 186.850 0.000 187.130 0.280 ;
    END
  END x0[0]
  PIN x0[10]
    DIRECTION INPUT ;
    USE SIGNAL ;
    ANTENNAGATEAREA 0.196500 ;
    PORT
      LAYER met2 ;
        RECT 65.410 0.000 65.690 0.280 ;
    END
  END x0[10]
  PIN x0[11]
    DIRECTION INPUT ;
    USE SIGNAL ;
    ANTENNAGATEAREA 0.196500 ;
    PORT
      LAYER met2 ;
        RECT 61.730 376.985 62.010 377.265 ;
    END
  END x0[11]
  PIN x0[12]
    DIRECTION INPUT ;
    USE SIGNAL ;
    ANTENNAGATEAREA 0.196500 ;
    PORT
      LAYER met2 ;
        RECT 71.850 376.985 72.130 377.265 ;
    END
  END x0[12]
  PIN x0[13]
    DIRECTION INPUT ;
    USE SIGNAL ;
    ANTENNAGATEAREA 0.196500 ;
    PORT
      LAYER met2 ;
        RECT 81.970 376.985 82.250 377.265 ;
    END
  END x0[13]
  PIN x0[14]
    DIRECTION INPUT ;
    USE SIGNAL ;
    ANTENNAGATEAREA 0.196500 ;
    PORT
      LAYER met2 ;
        RECT 55.290 376.985 55.570 377.265 ;
    END
  END x0[14]
  PIN x0[15]
    DIRECTION INPUT ;
    USE SIGNAL ;
    ANTENNAGATEAREA 0.196500 ;
    PORT
      LAYER met2 ;
        RECT 66.330 376.985 66.610 377.265 ;
    END
  END x0[15]
  PIN x0[16]
    DIRECTION INPUT ;
    USE SIGNAL ;
    ANTENNAGATEAREA 0.196500 ;
    PORT
      LAYER met3 ;
        RECT 0.000 295.160 0.600 295.760 ;
    END
  END x0[16]
  PIN x0[17]
    DIRECTION INPUT ;
    USE SIGNAL ;
    ANTENNAGATEAREA 0.196500 ;
    PORT
      LAYER met2 ;
        RECT 58.970 376.985 59.250 377.265 ;
    END
  END x0[17]
  PIN x0[18]
    DIRECTION INPUT ;
    USE SIGNAL ;
    ANTENNAGATEAREA 0.196500 ;
    PORT
      LAYER met2 ;
        RECT 33.210 376.985 33.490 377.265 ;
    END
  END x0[18]
  PIN x0[19]
    DIRECTION INPUT ;
    USE SIGNAL ;
    ANTENNAGATEAREA 0.196500 ;
    PORT
      LAYER met2 ;
        RECT 44.250 376.985 44.530 377.265 ;
    END
  END x0[19]
  PIN x0[1]
    DIRECTION INPUT ;
    USE SIGNAL ;
    ANTENNAGATEAREA 0.196500 ;
    PORT
      LAYER met2 ;
        RECT 164.770 0.000 165.050 0.280 ;
    END
  END x0[1]
  PIN x0[20]
    DIRECTION INPUT ;
    USE SIGNAL ;
    ANTENNAGATEAREA 0.196500 ;
    PORT
      LAYER met3 ;
        RECT 0.000 314.200 0.600 314.800 ;
    END
  END x0[20]
  PIN x0[21]
    DIRECTION INPUT ;
    USE SIGNAL ;
    ANTENNAGATEAREA 0.196500 ;
    PORT
      LAYER met3 ;
        RECT 0.000 306.040 0.600 306.640 ;
    END
  END x0[21]
  PIN x0[22]
    DIRECTION INPUT ;
    USE SIGNAL ;
    ANTENNAGATEAREA 0.196500 ;
    PORT
      LAYER met3 ;
        RECT 0.000 246.200 0.600 246.800 ;
    END
  END x0[22]
  PIN x0[23]
    DIRECTION INPUT ;
    USE SIGNAL ;
    ANTENNAGATEAREA 0.196500 ;
    PORT
      LAYER met3 ;
        RECT 0.000 229.880 0.600 230.480 ;
    END
  END x0[23]
  PIN x0[24]
    DIRECTION INPUT ;
    USE SIGNAL ;
    ANTENNAGATEAREA 0.196500 ;
    PORT
      LAYER met3 ;
        RECT 0.000 214.920 0.600 215.520 ;
    END
  END x0[24]
  PIN x0[25]
    DIRECTION INPUT ;
    USE SIGNAL ;
    ANTENNAGATEAREA 0.196500 ;
    PORT
      LAYER met3 ;
        RECT 0.000 190.440 0.600 191.040 ;
    END
  END x0[25]
  PIN x0[26]
    DIRECTION INPUT ;
    USE SIGNAL ;
    ANTENNAGATEAREA 0.196500 ;
    PORT
      LAYER met3 ;
        RECT 0.000 68.040 0.600 68.640 ;
    END
  END x0[26]
  PIN x0[27]
    DIRECTION INPUT ;
    USE SIGNAL ;
    ANTENNAGATEAREA 0.196500 ;
    PORT
      LAYER met3 ;
        RECT 0.000 55.800 0.600 56.400 ;
    END
  END x0[27]
  PIN x0[28]
    DIRECTION INPUT ;
    USE SIGNAL ;
    ANTENNAGATEAREA 0.196500 ;
    PORT
      LAYER met3 ;
        RECT 0.000 46.280 0.600 46.880 ;
    END
  END x0[28]
  PIN x0[29]
    DIRECTION INPUT ;
    USE SIGNAL ;
    ANTENNAGATEAREA 0.196500 ;
    PORT
      LAYER met3 ;
        RECT 0.000 32.680 0.600 33.280 ;
    END
  END x0[29]
  PIN x0[2]
    DIRECTION INPUT ;
    USE SIGNAL ;
    ANTENNAGATEAREA 0.196500 ;
    PORT
      LAYER met2 ;
        RECT 205.250 0.000 205.530 0.280 ;
    END
  END x0[2]
  PIN x0[30]
    DIRECTION INPUT ;
    USE SIGNAL ;
    ANTENNAGATEAREA 0.196500 ;
    PORT
      LAYER met3 ;
        RECT 0.000 39.480 0.600 40.080 ;
    END
  END x0[30]
  PIN x0[31]
    DIRECTION INPUT ;
    USE SIGNAL ;
    ANTENNAGATEAREA 0.196500 ;
    PORT
      LAYER met3 ;
        RECT 0.000 78.920 0.600 79.520 ;
    END
  END x0[31]
  PIN x0[3]
    DIRECTION INPUT ;
    USE SIGNAL ;
    ANTENNAGATEAREA 0.196500 ;
    PORT
      LAYER met2 ;
        RECT 261.370 0.000 261.650 0.280 ;
    END
  END x0[3]
  PIN x0[4]
    DIRECTION INPUT ;
    USE SIGNAL ;
    ANTENNAGATEAREA 0.196500 ;
    PORT
      LAYER met2 ;
        RECT 272.410 0.000 272.690 0.280 ;
    END
  END x0[4]
  PIN x0[5]
    DIRECTION INPUT ;
    USE SIGNAL ;
    ANTENNAGATEAREA 0.196500 ;
    PORT
      LAYER met2 ;
        RECT 249.410 0.000 249.690 0.280 ;
    END
  END x0[5]
  PIN x0[6]
    DIRECTION INPUT ;
    USE SIGNAL ;
    ANTENNAGATEAREA 0.196500 ;
    PORT
      LAYER met2 ;
        RECT 236.530 0.000 236.810 0.280 ;
    END
  END x0[6]
  PIN x0[7]
    DIRECTION INPUT ;
    USE SIGNAL ;
    ANTENNAGATEAREA 0.196500 ;
    PORT
      LAYER met2 ;
        RECT 257.690 0.000 257.970 0.280 ;
    END
  END x0[7]
  PIN x0[8]
    DIRECTION INPUT ;
    USE SIGNAL ;
    ANTENNAGATEAREA 0.196500 ;
    PORT
      LAYER met2 ;
        RECT 98.530 0.000 98.810 0.280 ;
    END
  END x0[8]
  PIN x0[9]
    DIRECTION INPUT ;
    USE SIGNAL ;
    ANTENNAGATEAREA 0.196500 ;
    PORT
      LAYER met2 ;
        RECT 72.770 0.000 73.050 0.280 ;
    END
  END x0[9]
  PIN x1[0]
    DIRECTION INPUT ;
    USE SIGNAL ;
    ANTENNAGATEAREA 0.196500 ;
    PORT
      LAYER met2 ;
        RECT 185.930 0.000 186.210 0.280 ;
    END
  END x1[0]
  PIN x1[10]
    DIRECTION INPUT ;
    USE SIGNAL ;
    ANTENNAGATEAREA 0.196500 ;
    PORT
      LAYER met2 ;
        RECT 64.490 0.000 64.770 0.280 ;
    END
  END x1[10]
  PIN x1[11]
    DIRECTION INPUT ;
    USE SIGNAL ;
    ANTENNAGATEAREA 0.196500 ;
    PORT
      LAYER met2 ;
        RECT 62.650 376.985 62.930 377.265 ;
    END
  END x1[11]
  PIN x1[12]
    DIRECTION INPUT ;
    USE SIGNAL ;
    ANTENNAGATEAREA 0.196500 ;
    PORT
      LAYER met2 ;
        RECT 67.250 376.985 67.530 377.265 ;
    END
  END x1[12]
  PIN x1[13]
    DIRECTION INPUT ;
    USE SIGNAL ;
    ANTENNAGATEAREA 0.196500 ;
    PORT
      LAYER met2 ;
        RECT 81.050 376.985 81.330 377.265 ;
    END
  END x1[13]
  PIN x1[14]
    DIRECTION INPUT ;
    USE SIGNAL ;
    ANTENNAGATEAREA 0.196500 ;
    PORT
      LAYER met2 ;
        RECT 54.370 376.985 54.650 377.265 ;
    END
  END x1[14]
  PIN x1[15]
    DIRECTION INPUT ;
    USE SIGNAL ;
    ANTENNAGATEAREA 0.196500 ;
    PORT
      LAYER met2 ;
        RECT 65.410 376.985 65.690 377.265 ;
    END
  END x1[15]
  PIN x1[16]
    DIRECTION INPUT ;
    USE SIGNAL ;
    ANTENNAGATEAREA 0.196500 ;
    PORT
      LAYER met3 ;
        RECT 0.000 296.520 0.600 297.120 ;
    END
  END x1[16]
  PIN x1[17]
    DIRECTION INPUT ;
    USE SIGNAL ;
    ANTENNAGATEAREA 0.196500 ;
    PORT
      LAYER met2 ;
        RECT 57.130 376.985 57.410 377.265 ;
    END
  END x1[17]
  PIN x1[18]
    DIRECTION INPUT ;
    USE SIGNAL ;
    ANTENNAGATEAREA 0.196500 ;
    PORT
      LAYER met2 ;
        RECT 34.130 376.985 34.410 377.265 ;
    END
  END x1[18]
  PIN x1[19]
    DIRECTION INPUT ;
    USE SIGNAL ;
    ANTENNAGATEAREA 0.196500 ;
    PORT
      LAYER met2 ;
        RECT 43.330 376.985 43.610 377.265 ;
    END
  END x1[19]
  PIN x1[1]
    DIRECTION INPUT ;
    USE SIGNAL ;
    ANTENNAGATEAREA 0.196500 ;
    PORT
      LAYER met2 ;
        RECT 163.850 0.000 164.130 0.280 ;
    END
  END x1[1]
  PIN x1[20]
    DIRECTION INPUT ;
    USE SIGNAL ;
    ANTENNAGATEAREA 0.196500 ;
    PORT
      LAYER met3 ;
        RECT 0.000 300.600 0.600 301.200 ;
    END
  END x1[20]
  PIN x1[21]
    DIRECTION INPUT ;
    USE SIGNAL ;
    ANTENNAGATEAREA 0.196500 ;
    PORT
      LAYER met3 ;
        RECT 0.000 304.680 0.600 305.280 ;
    END
  END x1[21]
  PIN x1[22]
    DIRECTION INPUT ;
    USE SIGNAL ;
    ANTENNAGATEAREA 0.196500 ;
    PORT
      LAYER met3 ;
        RECT 0.000 250.280 0.600 250.880 ;
    END
  END x1[22]
  PIN x1[23]
    DIRECTION INPUT ;
    USE SIGNAL ;
    ANTENNAGATEAREA 0.196500 ;
    PORT
      LAYER met3 ;
        RECT 0.000 231.240 0.600 231.840 ;
    END
  END x1[23]
  PIN x1[24]
    DIRECTION INPUT ;
    USE SIGNAL ;
    ANTENNAGATEAREA 0.196500 ;
    PORT
      LAYER met3 ;
        RECT 0.000 216.280 0.600 216.880 ;
    END
  END x1[24]
  PIN x1[25]
    DIRECTION INPUT ;
    USE SIGNAL ;
    ANTENNAGATEAREA 0.196500 ;
    PORT
      LAYER met3 ;
        RECT 0.000 191.800 0.600 192.400 ;
    END
  END x1[25]
  PIN x1[26]
    DIRECTION INPUT ;
    USE SIGNAL ;
    ANTENNAGATEAREA 0.196500 ;
    PORT
      LAYER met3 ;
        RECT 0.000 69.400 0.600 70.000 ;
    END
  END x1[26]
  PIN x1[27]
    DIRECTION INPUT ;
    USE SIGNAL ;
    ANTENNAGATEAREA 0.196500 ;
    PORT
      LAYER met3 ;
        RECT 0.000 57.160 0.600 57.760 ;
    END
  END x1[27]
  PIN x1[28]
    DIRECTION INPUT ;
    USE SIGNAL ;
    ANTENNAGATEAREA 0.196500 ;
    PORT
      LAYER met3 ;
        RECT 0.000 50.360 0.600 50.960 ;
    END
  END x1[28]
  PIN x1[29]
    DIRECTION INPUT ;
    USE SIGNAL ;
    ANTENNAGATEAREA 0.196500 ;
    PORT
      LAYER met3 ;
        RECT 0.000 34.040 0.600 34.640 ;
    END
  END x1[29]
  PIN x1[2]
    DIRECTION INPUT ;
    USE SIGNAL ;
    ANTENNAGATEAREA 0.196500 ;
    PORT
      LAYER met2 ;
        RECT 204.330 0.000 204.610 0.280 ;
    END
  END x1[2]
  PIN x1[30]
    DIRECTION INPUT ;
    USE SIGNAL ;
    ANTENNAGATEAREA 0.196500 ;
    PORT
      LAYER met3 ;
        RECT 0.000 38.120 0.600 38.720 ;
    END
  END x1[30]
  PIN x1[31]
    DIRECTION INPUT ;
    USE SIGNAL ;
    ANTENNAGATEAREA 0.196500 ;
    PORT
      LAYER met3 ;
        RECT 0.000 80.280 0.600 80.880 ;
    END
  END x1[31]
  PIN x1[3]
    DIRECTION INPUT ;
    USE SIGNAL ;
    ANTENNAGATEAREA 0.196500 ;
    PORT
      LAYER met2 ;
        RECT 260.450 0.000 260.730 0.280 ;
    END
  END x1[3]
  PIN x1[4]
    DIRECTION INPUT ;
    USE SIGNAL ;
    ANTENNAGATEAREA 0.196500 ;
    PORT
      LAYER met2 ;
        RECT 271.490 0.000 271.770 0.280 ;
    END
  END x1[4]
  PIN x1[5]
    DIRECTION INPUT ;
    USE SIGNAL ;
    ANTENNAGATEAREA 0.196500 ;
    PORT
      LAYER met2 ;
        RECT 248.490 0.000 248.770 0.280 ;
    END
  END x1[5]
  PIN x1[6]
    DIRECTION INPUT ;
    USE SIGNAL ;
    ANTENNAGATEAREA 0.196500 ;
    PORT
      LAYER met2 ;
        RECT 235.610 0.000 235.890 0.280 ;
    END
  END x1[6]
  PIN x1[7]
    DIRECTION INPUT ;
    USE SIGNAL ;
    ANTENNAGATEAREA 0.196500 ;
    PORT
      LAYER met2 ;
        RECT 256.770 0.000 257.050 0.280 ;
    END
  END x1[7]
  PIN x1[8]
    DIRECTION INPUT ;
    USE SIGNAL ;
    ANTENNAGATEAREA 0.196500 ;
    PORT
      LAYER met2 ;
        RECT 97.610 0.000 97.890 0.280 ;
    END
  END x1[8]
  PIN x1[9]
    DIRECTION INPUT ;
    USE SIGNAL ;
    ANTENNAGATEAREA 0.196500 ;
    PORT
      LAYER met2 ;
        RECT 71.850 0.000 72.130 0.280 ;
    END
  END x1[9]
  PIN x2[0]
    DIRECTION INPUT ;
    USE SIGNAL ;
    ANTENNAGATEAREA 0.196500 ;
    PORT
      LAYER met2 ;
        RECT 184.090 0.000 184.370 0.280 ;
    END
  END x2[0]
  PIN x2[10]
    DIRECTION INPUT ;
    USE SIGNAL ;
    ANTENNAGATEAREA 0.196500 ;
    PORT
      LAYER met3 ;
        RECT 0.000 40.840 0.600 41.440 ;
    END
  END x2[10]
  PIN x2[11]
    DIRECTION INPUT ;
    USE SIGNAL ;
    ANTENNAGATEAREA 0.196500 ;
    PORT
      LAYER met2 ;
        RECT 64.490 376.985 64.770 377.265 ;
    END
  END x2[11]
  PIN x2[12]
    DIRECTION INPUT ;
    USE SIGNAL ;
    ANTENNAGATEAREA 0.196500 ;
    PORT
      LAYER met2 ;
        RECT 70.930 376.985 71.210 377.265 ;
    END
  END x2[12]
  PIN x2[13]
    DIRECTION INPUT ;
    USE SIGNAL ;
    ANTENNAGATEAREA 0.196500 ;
    PORT
      LAYER met2 ;
        RECT 79.210 376.985 79.490 377.265 ;
    END
  END x2[13]
  PIN x2[14]
    DIRECTION INPUT ;
    USE SIGNAL ;
    ANTENNAGATEAREA 0.196500 ;
    PORT
      LAYER met2 ;
        RECT 58.050 376.985 58.330 377.265 ;
    END
  END x2[14]
  PIN x2[15]
    DIRECTION INPUT ;
    USE SIGNAL ;
    ANTENNAGATEAREA 0.196500 ;
    PORT
      LAYER met2 ;
        RECT 68.170 376.985 68.450 377.265 ;
    END
  END x2[15]
  PIN x2[16]
    DIRECTION INPUT ;
    USE SIGNAL ;
    ANTENNAGATEAREA 0.196500 ;
    PORT
      LAYER met3 ;
        RECT 0.000 303.320 0.600 303.920 ;
    END
  END x2[16]
  PIN x2[17]
    DIRECTION INPUT ;
    USE SIGNAL ;
    ANTENNAGATEAREA 0.196500 ;
    PORT
      LAYER met2 ;
        RECT 53.450 376.985 53.730 377.265 ;
    END
  END x2[17]
  PIN x2[18]
    DIRECTION INPUT ;
    USE SIGNAL ;
    ANTENNAGATEAREA 0.196500 ;
    PORT
      LAYER met2 ;
        RECT 35.050 376.985 35.330 377.265 ;
    END
  END x2[18]
  PIN x2[19]
    DIRECTION INPUT ;
    USE SIGNAL ;
    ANTENNAGATEAREA 0.196500 ;
    PORT
      LAYER met2 ;
        RECT 45.170 376.985 45.450 377.265 ;
    END
  END x2[19]
  PIN x2[1]
    DIRECTION INPUT ;
    USE SIGNAL ;
    ANTENNAGATEAREA 0.196500 ;
    PORT
      LAYER met2 ;
        RECT 173.970 0.000 174.250 0.280 ;
    END
  END x2[1]
  PIN x2[20]
    DIRECTION INPUT ;
    USE SIGNAL ;
    ANTENNAGATEAREA 0.196500 ;
    PORT
      LAYER met3 ;
        RECT 0.000 299.240 0.600 299.840 ;
    END
  END x2[20]
  PIN x2[21]
    DIRECTION INPUT ;
    USE SIGNAL ;
    ANTENNAGATEAREA 0.196500 ;
    PORT
      LAYER met3 ;
        RECT 0.000 308.760 0.600 309.360 ;
    END
  END x2[21]
  PIN x2[22]
    DIRECTION INPUT ;
    USE SIGNAL ;
    ANTENNAGATEAREA 0.196500 ;
    PORT
      LAYER met3 ;
        RECT 0.000 248.920 0.600 249.520 ;
    END
  END x2[22]
  PIN x2[23]
    DIRECTION INPUT ;
    USE SIGNAL ;
    ANTENNAGATEAREA 0.196500 ;
    PORT
      LAYER met3 ;
        RECT 0.000 223.080 0.600 223.680 ;
    END
  END x2[23]
  PIN x2[24]
    DIRECTION INPUT ;
    USE SIGNAL ;
    ANTENNAGATEAREA 0.196500 ;
    PORT
      LAYER met3 ;
        RECT 0.000 212.200 0.600 212.800 ;
    END
  END x2[24]
  PIN x2[25]
    DIRECTION INPUT ;
    USE SIGNAL ;
    ANTENNAGATEAREA 0.196500 ;
    PORT
      LAYER met3 ;
        RECT 0.000 187.720 0.600 188.320 ;
    END
  END x2[25]
  PIN x2[26]
    DIRECTION INPUT ;
    USE SIGNAL ;
    ANTENNAGATEAREA 0.196500 ;
    PORT
      LAYER met3 ;
        RECT 0.000 65.320 0.600 65.920 ;
    END
  END x2[26]
  PIN x2[27]
    DIRECTION INPUT ;
    USE SIGNAL ;
    ANTENNAGATEAREA 0.196500 ;
    PORT
      LAYER met3 ;
        RECT 0.000 59.880 0.600 60.480 ;
    END
  END x2[27]
  PIN x2[28]
    DIRECTION INPUT ;
    USE SIGNAL ;
    ANTENNAGATEAREA 0.196500 ;
    PORT
      LAYER met3 ;
        RECT 0.000 49.000 0.600 49.600 ;
    END
  END x2[28]
  PIN x2[29]
    DIRECTION INPUT ;
    USE SIGNAL ;
    ANTENNAGATEAREA 0.196500 ;
    PORT
      LAYER met3 ;
        RECT 0.000 36.760 0.600 37.360 ;
    END
  END x2[29]
  PIN x2[2]
    DIRECTION INPUT ;
    USE SIGNAL ;
    ANTENNAGATEAREA 0.196500 ;
    PORT
      LAYER met2 ;
        RECT 203.410 0.000 203.690 0.280 ;
    END
  END x2[2]
  PIN x2[30]
    DIRECTION INPUT ;
    USE SIGNAL ;
    ANTENNAGATEAREA 0.196500 ;
    PORT
      LAYER met3 ;
        RECT 0.000 43.560 0.600 44.160 ;
    END
  END x2[30]
  PIN x2[31]
    DIRECTION INPUT ;
    USE SIGNAL ;
    ANTENNAGATEAREA 0.196500 ;
    PORT
      LAYER met3 ;
        RECT 0.000 76.200 0.600 76.800 ;
    END
  END x2[31]
  PIN x2[3]
    DIRECTION INPUT ;
    USE SIGNAL ;
    ANTENNAGATEAREA 0.196500 ;
    PORT
      LAYER met2 ;
        RECT 259.530 0.000 259.810 0.280 ;
    END
  END x2[3]
  PIN x2[4]
    DIRECTION INPUT ;
    USE SIGNAL ;
    ANTENNAGATEAREA 0.196500 ;
    PORT
      LAYER met2 ;
        RECT 267.810 0.000 268.090 0.280 ;
    END
  END x2[4]
  PIN x2[5]
    DIRECTION INPUT ;
    USE SIGNAL ;
    ANTENNAGATEAREA 0.196500 ;
    PORT
      LAYER met2 ;
        RECT 247.570 0.000 247.850 0.280 ;
    END
  END x2[5]
  PIN x2[6]
    DIRECTION INPUT ;
    USE SIGNAL ;
    ANTENNAGATEAREA 0.196500 ;
    PORT
      LAYER met2 ;
        RECT 238.370 0.000 238.650 0.280 ;
    END
  END x2[6]
  PIN x2[7]
    DIRECTION INPUT ;
    USE SIGNAL ;
    ANTENNAGATEAREA 0.196500 ;
    PORT
      LAYER met2 ;
        RECT 255.850 0.000 256.130 0.280 ;
    END
  END x2[7]
  PIN x2[8]
    DIRECTION INPUT ;
    USE SIGNAL ;
    ANTENNAGATEAREA 0.196500 ;
    PORT
      LAYER met2 ;
        RECT 96.690 0.000 96.970 0.280 ;
    END
  END x2[8]
  PIN x2[9]
    DIRECTION INPUT ;
    USE SIGNAL ;
    ANTENNAGATEAREA 0.196500 ;
    PORT
      LAYER met2 ;
        RECT 77.370 0.000 77.650 0.280 ;
    END
  END x2[9]
  PIN x3[0]
    DIRECTION INPUT ;
    USE SIGNAL ;
    ANTENNAGATEAREA 0.196500 ;
    PORT
      LAYER met2 ;
        RECT 183.170 0.000 183.450 0.280 ;
    END
  END x3[0]
  PIN x3[10]
    DIRECTION INPUT ;
    USE SIGNAL ;
    ANTENNAGATEAREA 0.196500 ;
    PORT
      LAYER met3 ;
        RECT 0.000 35.400 0.600 36.000 ;
    END
  END x3[10]
  PIN x3[11]
    DIRECTION INPUT ;
    USE SIGNAL ;
    ANTENNAGATEAREA 0.196500 ;
    PORT
      LAYER met2 ;
        RECT 63.570 376.985 63.850 377.265 ;
    END
  END x3[11]
  PIN x3[12]
    DIRECTION INPUT ;
    USE SIGNAL ;
    ANTENNAGATEAREA 0.196500 ;
    PORT
      LAYER met2 ;
        RECT 70.010 376.985 70.290 377.265 ;
    END
  END x3[12]
  PIN x3[13]
    DIRECTION INPUT ;
    USE SIGNAL ;
    ANTENNAGATEAREA 0.196500 ;
    PORT
      LAYER met2 ;
        RECT 78.290 376.985 78.570 377.265 ;
    END
  END x3[13]
  PIN x3[14]
    DIRECTION INPUT ;
    USE SIGNAL ;
    ANTENNAGATEAREA 0.196500 ;
    PORT
      LAYER met2 ;
        RECT 56.210 376.985 56.490 377.265 ;
    END
  END x3[14]
  PIN x3[15]
    DIRECTION INPUT ;
    USE SIGNAL ;
    ANTENNAGATEAREA 0.196500 ;
    PORT
      LAYER met2 ;
        RECT 69.090 376.985 69.370 377.265 ;
    END
  END x3[15]
  PIN x3[16]
    DIRECTION INPUT ;
    USE SIGNAL ;
    ANTENNAGATEAREA 0.196500 ;
    PORT
      LAYER met3 ;
        RECT 0.000 301.960 0.600 302.560 ;
    END
  END x3[16]
  PIN x3[17]
    DIRECTION INPUT ;
    USE SIGNAL ;
    ANTENNAGATEAREA 0.196500 ;
    PORT
      LAYER met2 ;
        RECT 52.530 376.985 52.810 377.265 ;
    END
  END x3[17]
  PIN x3[18]
    DIRECTION INPUT ;
    USE SIGNAL ;
    ANTENNAGATEAREA 0.196500 ;
    PORT
      LAYER met2 ;
        RECT 35.970 376.985 36.250 377.265 ;
    END
  END x3[18]
  PIN x3[19]
    DIRECTION INPUT ;
    USE SIGNAL ;
    ANTENNAGATEAREA 0.196500 ;
    PORT
      LAYER met2 ;
        RECT 46.090 376.985 46.370 377.265 ;
    END
  END x3[19]
  PIN x3[1]
    DIRECTION INPUT ;
    USE SIGNAL ;
    ANTENNAGATEAREA 0.196500 ;
    PORT
      LAYER met2 ;
        RECT 173.050 0.000 173.330 0.280 ;
    END
  END x3[1]
  PIN x3[20]
    DIRECTION INPUT ;
    USE SIGNAL ;
    ANTENNAGATEAREA 0.196500 ;
    PORT
      LAYER met3 ;
        RECT 0.000 297.880 0.600 298.480 ;
    END
  END x3[20]
  PIN x3[21]
    DIRECTION INPUT ;
    USE SIGNAL ;
    ANTENNAGATEAREA 0.196500 ;
    PORT
      LAYER met3 ;
        RECT 0.000 307.400 0.600 308.000 ;
    END
  END x3[21]
  PIN x3[22]
    DIRECTION INPUT ;
    USE SIGNAL ;
    ANTENNAGATEAREA 0.196500 ;
    PORT
      LAYER met3 ;
        RECT 0.000 247.560 0.600 248.160 ;
    END
  END x3[22]
  PIN x3[23]
    DIRECTION INPUT ;
    USE SIGNAL ;
    ANTENNAGATEAREA 0.196500 ;
    PORT
      LAYER met3 ;
        RECT 0.000 224.440 0.600 225.040 ;
    END
  END x3[23]
  PIN x3[24]
    DIRECTION INPUT ;
    USE SIGNAL ;
    ANTENNAGATEAREA 0.196500 ;
    PORT
      LAYER met3 ;
        RECT 0.000 213.560 0.600 214.160 ;
    END
  END x3[24]
  PIN x3[25]
    DIRECTION INPUT ;
    USE SIGNAL ;
    ANTENNAGATEAREA 0.196500 ;
    PORT
      LAYER met3 ;
        RECT 0.000 189.080 0.600 189.680 ;
    END
  END x3[25]
  PIN x3[26]
    DIRECTION INPUT ;
    USE SIGNAL ;
    ANTENNAGATEAREA 0.196500 ;
    PORT
      LAYER met3 ;
        RECT 0.000 66.680 0.600 67.280 ;
    END
  END x3[26]
  PIN x3[27]
    DIRECTION INPUT ;
    USE SIGNAL ;
    ANTENNAGATEAREA 0.196500 ;
    PORT
      LAYER met3 ;
        RECT 0.000 58.520 0.600 59.120 ;
    END
  END x3[27]
  PIN x3[28]
    DIRECTION INPUT ;
    USE SIGNAL ;
    ANTENNAGATEAREA 0.196500 ;
    PORT
      LAYER met3 ;
        RECT 0.000 47.640 0.600 48.240 ;
    END
  END x3[28]
  PIN x3[29]
    DIRECTION INPUT ;
    USE SIGNAL ;
    ANTENNAGATEAREA 0.196500 ;
    PORT
      LAYER met3 ;
        RECT 0.000 44.920 0.600 45.520 ;
    END
  END x3[29]
  PIN x3[2]
    DIRECTION INPUT ;
    USE SIGNAL ;
    ANTENNAGATEAREA 0.196500 ;
    PORT
      LAYER met2 ;
        RECT 202.490 0.000 202.770 0.280 ;
    END
  END x3[2]
  PIN x3[30]
    DIRECTION INPUT ;
    USE SIGNAL ;
    ANTENNAGATEAREA 0.196500 ;
    PORT
      LAYER met3 ;
        RECT 0.000 42.200 0.600 42.800 ;
    END
  END x3[30]
  PIN x3[31]
    DIRECTION INPUT ;
    USE SIGNAL ;
    ANTENNAGATEAREA 0.196500 ;
    PORT
      LAYER met3 ;
        RECT 0.000 77.560 0.600 78.160 ;
    END
  END x3[31]
  PIN x3[3]
    DIRECTION INPUT ;
    USE SIGNAL ;
    ANTENNAGATEAREA 0.196500 ;
    PORT
      LAYER met2 ;
        RECT 258.610 0.000 258.890 0.280 ;
    END
  END x3[3]
  PIN x3[4]
    DIRECTION INPUT ;
    USE SIGNAL ;
    ANTENNAGATEAREA 0.196500 ;
    PORT
      LAYER met2 ;
        RECT 266.890 0.000 267.170 0.280 ;
    END
  END x3[4]
  PIN x3[5]
    DIRECTION INPUT ;
    USE SIGNAL ;
    ANTENNAGATEAREA 0.196500 ;
    PORT
      LAYER met2 ;
        RECT 246.650 0.000 246.930 0.280 ;
    END
  END x3[5]
  PIN x3[6]
    DIRECTION INPUT ;
    USE SIGNAL ;
    ANTENNAGATEAREA 0.196500 ;
    PORT
      LAYER met2 ;
        RECT 237.450 0.000 237.730 0.280 ;
    END
  END x3[6]
  PIN x3[7]
    DIRECTION INPUT ;
    USE SIGNAL ;
    ANTENNAGATEAREA 0.196500 ;
    PORT
      LAYER met2 ;
        RECT 254.930 0.000 255.210 0.280 ;
    END
  END x3[7]
  PIN x3[8]
    DIRECTION INPUT ;
    USE SIGNAL ;
    ANTENNAGATEAREA 0.196500 ;
    PORT
      LAYER met2 ;
        RECT 95.770 0.000 96.050 0.280 ;
    END
  END x3[8]
  PIN x3[9]
    DIRECTION INPUT ;
    USE SIGNAL ;
    ANTENNAGATEAREA 0.196500 ;
    PORT
      LAYER met2 ;
        RECT 76.450 0.000 76.730 0.280 ;
    END
  END x3[9]
  OBS
      LAYER nwell ;
        RECT 5.330 10.795 360.830 364.565 ;
      LAYER li1 ;
        RECT 5.520 10.795 360.640 364.565 ;
      LAYER met1 ;
        RECT 0.990 6.840 364.250 365.800 ;
      LAYER met2 ;
        RECT 1.010 376.705 25.570 376.985 ;
        RECT 26.410 376.705 26.490 376.985 ;
        RECT 27.330 376.705 27.410 376.985 ;
        RECT 28.250 376.705 28.330 376.985 ;
        RECT 29.170 376.705 32.930 376.985 ;
        RECT 33.770 376.705 33.850 376.985 ;
        RECT 34.690 376.705 34.770 376.985 ;
        RECT 35.610 376.705 35.690 376.985 ;
        RECT 36.530 376.705 36.610 376.985 ;
        RECT 37.450 376.705 37.530 376.985 ;
        RECT 38.370 376.705 41.210 376.985 ;
        RECT 42.050 376.705 42.130 376.985 ;
        RECT 42.970 376.705 43.050 376.985 ;
        RECT 43.890 376.705 43.970 376.985 ;
        RECT 44.810 376.705 44.890 376.985 ;
        RECT 45.730 376.705 45.810 376.985 ;
        RECT 46.650 376.705 52.250 376.985 ;
        RECT 53.090 376.705 53.170 376.985 ;
        RECT 54.010 376.705 54.090 376.985 ;
        RECT 54.930 376.705 55.010 376.985 ;
        RECT 55.850 376.705 55.930 376.985 ;
        RECT 56.770 376.705 56.850 376.985 ;
        RECT 57.690 376.705 57.770 376.985 ;
        RECT 58.610 376.705 58.690 376.985 ;
        RECT 59.530 376.705 61.450 376.985 ;
        RECT 62.290 376.705 62.370 376.985 ;
        RECT 63.210 376.705 63.290 376.985 ;
        RECT 64.130 376.705 64.210 376.985 ;
        RECT 65.050 376.705 65.130 376.985 ;
        RECT 65.970 376.705 66.050 376.985 ;
        RECT 66.890 376.705 66.970 376.985 ;
        RECT 67.810 376.705 67.890 376.985 ;
        RECT 68.730 376.705 68.810 376.985 ;
        RECT 69.650 376.705 69.730 376.985 ;
        RECT 70.570 376.705 70.650 376.985 ;
        RECT 71.490 376.705 71.570 376.985 ;
        RECT 72.410 376.705 78.010 376.985 ;
        RECT 78.850 376.705 78.930 376.985 ;
        RECT 79.770 376.705 80.770 376.985 ;
        RECT 81.610 376.705 81.690 376.985 ;
        RECT 82.530 376.705 364.230 376.985 ;
        RECT 1.010 0.560 364.230 376.705 ;
        RECT 1.010 0.070 64.210 0.560 ;
        RECT 65.050 0.070 65.130 0.560 ;
        RECT 65.970 0.070 71.570 0.560 ;
        RECT 72.410 0.070 72.490 0.560 ;
        RECT 73.330 0.070 74.330 0.560 ;
        RECT 75.170 0.070 75.250 0.560 ;
        RECT 76.090 0.070 76.170 0.560 ;
        RECT 77.010 0.070 77.090 0.560 ;
        RECT 77.930 0.070 95.490 0.560 ;
        RECT 96.330 0.070 96.410 0.560 ;
        RECT 97.250 0.070 97.330 0.560 ;
        RECT 98.170 0.070 98.250 0.560 ;
        RECT 99.090 0.070 107.450 0.560 ;
        RECT 108.290 0.070 108.370 0.560 ;
        RECT 109.210 0.070 109.290 0.560 ;
        RECT 110.130 0.070 110.210 0.560 ;
        RECT 111.050 0.070 119.410 0.560 ;
        RECT 120.250 0.070 120.330 0.560 ;
        RECT 121.170 0.070 121.250 0.560 ;
        RECT 122.090 0.070 122.170 0.560 ;
        RECT 123.010 0.070 129.530 0.560 ;
        RECT 130.370 0.070 130.450 0.560 ;
        RECT 131.290 0.070 131.370 0.560 ;
        RECT 132.210 0.070 132.290 0.560 ;
        RECT 133.130 0.070 163.570 0.560 ;
        RECT 164.410 0.070 164.490 0.560 ;
        RECT 165.330 0.070 172.770 0.560 ;
        RECT 173.610 0.070 173.690 0.560 ;
        RECT 174.530 0.070 182.890 0.560 ;
        RECT 183.730 0.070 183.810 0.560 ;
        RECT 184.650 0.070 185.650 0.560 ;
        RECT 186.490 0.070 186.570 0.560 ;
        RECT 187.410 0.070 189.330 0.560 ;
        RECT 190.170 0.070 190.250 0.560 ;
        RECT 191.090 0.070 191.170 0.560 ;
        RECT 192.010 0.070 192.090 0.560 ;
        RECT 192.930 0.070 193.010 0.560 ;
        RECT 193.850 0.070 193.930 0.560 ;
        RECT 194.770 0.070 194.850 0.560 ;
        RECT 195.690 0.070 195.770 0.560 ;
        RECT 196.610 0.070 196.690 0.560 ;
        RECT 197.530 0.070 197.610 0.560 ;
        RECT 198.450 0.070 198.530 0.560 ;
        RECT 199.370 0.070 199.450 0.560 ;
        RECT 200.290 0.070 200.370 0.560 ;
        RECT 201.210 0.070 201.290 0.560 ;
        RECT 202.130 0.070 202.210 0.560 ;
        RECT 203.050 0.070 203.130 0.560 ;
        RECT 203.970 0.070 204.050 0.560 ;
        RECT 204.890 0.070 204.970 0.560 ;
        RECT 205.810 0.070 207.730 0.560 ;
        RECT 208.570 0.070 208.650 0.560 ;
        RECT 209.490 0.070 209.570 0.560 ;
        RECT 210.410 0.070 210.490 0.560 ;
        RECT 211.330 0.070 211.410 0.560 ;
        RECT 212.250 0.070 212.330 0.560 ;
        RECT 213.170 0.070 213.250 0.560 ;
        RECT 214.090 0.070 214.170 0.560 ;
        RECT 215.010 0.070 215.090 0.560 ;
        RECT 215.930 0.070 216.010 0.560 ;
        RECT 216.850 0.070 216.930 0.560 ;
        RECT 217.770 0.070 217.850 0.560 ;
        RECT 218.690 0.070 218.770 0.560 ;
        RECT 219.610 0.070 219.690 0.560 ;
        RECT 220.530 0.070 220.610 0.560 ;
        RECT 221.450 0.070 221.530 0.560 ;
        RECT 222.370 0.070 222.450 0.560 ;
        RECT 223.290 0.070 223.370 0.560 ;
        RECT 224.210 0.070 224.290 0.560 ;
        RECT 225.130 0.070 225.210 0.560 ;
        RECT 226.050 0.070 226.130 0.560 ;
        RECT 226.970 0.070 227.050 0.560 ;
        RECT 227.890 0.070 227.970 0.560 ;
        RECT 228.810 0.070 228.890 0.560 ;
        RECT 229.730 0.070 231.650 0.560 ;
        RECT 232.490 0.070 232.570 0.560 ;
        RECT 233.410 0.070 233.490 0.560 ;
        RECT 234.330 0.070 234.410 0.560 ;
        RECT 235.250 0.070 235.330 0.560 ;
        RECT 236.170 0.070 236.250 0.560 ;
        RECT 237.090 0.070 237.170 0.560 ;
        RECT 238.010 0.070 238.090 0.560 ;
        RECT 238.930 0.070 239.010 0.560 ;
        RECT 239.850 0.070 239.930 0.560 ;
        RECT 240.770 0.070 240.850 0.560 ;
        RECT 241.690 0.070 241.770 0.560 ;
        RECT 242.610 0.070 246.370 0.560 ;
        RECT 247.210 0.070 247.290 0.560 ;
        RECT 248.130 0.070 248.210 0.560 ;
        RECT 249.050 0.070 249.130 0.560 ;
        RECT 249.970 0.070 254.650 0.560 ;
        RECT 255.490 0.070 255.570 0.560 ;
        RECT 256.410 0.070 256.490 0.560 ;
        RECT 257.330 0.070 257.410 0.560 ;
        RECT 258.250 0.070 258.330 0.560 ;
        RECT 259.170 0.070 259.250 0.560 ;
        RECT 260.090 0.070 260.170 0.560 ;
        RECT 261.010 0.070 261.090 0.560 ;
        RECT 261.930 0.070 266.610 0.560 ;
        RECT 267.450 0.070 267.530 0.560 ;
        RECT 268.370 0.070 271.210 0.560 ;
        RECT 272.050 0.070 272.130 0.560 ;
        RECT 272.970 0.070 364.230 0.560 ;
      LAYER met3 ;
        RECT 0.600 334.240 365.945 364.645 ;
        RECT 1.000 328.760 365.945 334.240 ;
        RECT 0.600 322.000 365.945 328.760 ;
        RECT 1.000 316.560 365.945 322.000 ;
        RECT 1.000 312.440 365.545 316.560 ;
        RECT 1.000 292.080 365.945 312.440 ;
        RECT 1.000 290.680 365.545 292.080 ;
        RECT 1.000 286.640 365.945 290.680 ;
        RECT 1.000 273.000 365.545 286.640 ;
        RECT 1.000 240.360 365.945 273.000 ;
        RECT 0.600 232.240 365.945 240.360 ;
        RECT 1.000 229.480 365.945 232.240 ;
        RECT 0.600 225.440 365.945 229.480 ;
        RECT 1.000 224.040 365.545 225.440 ;
        RECT 1.000 222.680 365.945 224.040 ;
        RECT 0.600 217.280 365.945 222.680 ;
        RECT 1.000 215.920 365.945 217.280 ;
        RECT 1.000 214.520 365.545 215.920 ;
        RECT 1.000 211.800 365.945 214.520 ;
        RECT 0.600 207.760 365.945 211.800 ;
        RECT 0.600 206.360 365.545 207.760 ;
        RECT 0.600 205.040 365.945 206.360 ;
        RECT 0.600 203.640 365.545 205.040 ;
        RECT 0.600 199.600 365.945 203.640 ;
        RECT 0.600 198.200 365.545 199.600 ;
        RECT 0.600 196.880 365.945 198.200 ;
        RECT 0.600 195.480 365.545 196.880 ;
        RECT 0.600 192.800 365.945 195.480 ;
        RECT 1.000 191.440 365.945 192.800 ;
        RECT 1.000 190.040 365.545 191.440 ;
        RECT 1.000 187.320 365.945 190.040 ;
        RECT 0.600 183.280 365.945 187.320 ;
        RECT 0.600 179.160 365.545 183.280 ;
        RECT 0.600 172.400 365.945 179.160 ;
        RECT 0.600 171.000 365.545 172.400 ;
        RECT 0.600 161.520 365.945 171.000 ;
        RECT 0.600 160.120 365.545 161.520 ;
        RECT 0.600 157.440 365.945 160.120 ;
        RECT 0.600 156.040 365.545 157.440 ;
        RECT 0.600 150.640 365.945 156.040 ;
        RECT 0.600 149.240 365.545 150.640 ;
        RECT 0.600 131.600 365.945 149.240 ;
        RECT 0.600 127.480 365.545 131.600 ;
        RECT 0.600 122.080 365.945 127.480 ;
        RECT 0.600 116.600 365.545 122.080 ;
        RECT 0.600 111.200 365.945 116.600 ;
        RECT 0.600 108.440 365.545 111.200 ;
        RECT 0.600 100.320 365.945 108.440 ;
        RECT 0.600 98.920 365.545 100.320 ;
        RECT 0.600 97.600 365.945 98.920 ;
        RECT 0.600 96.200 365.545 97.600 ;
        RECT 0.600 81.280 365.945 96.200 ;
        RECT 1.000 32.280 365.945 81.280 ;
        RECT 0.600 26.880 365.945 32.280 ;
        RECT 0.600 25.480 365.545 26.880 ;
        RECT 0.600 10.715 365.945 25.480 ;
      LAYER met4 ;
        RECT 10.415 15.815 20.640 296.985 ;
        RECT 23.040 15.815 23.940 296.985 ;
        RECT 26.340 15.815 174.240 296.985 ;
        RECT 176.640 15.815 177.540 296.985 ;
        RECT 179.940 15.815 327.840 296.985 ;
        RECT 330.240 15.815 331.140 296.985 ;
        RECT 333.540 15.815 335.505 296.985 ;
  END
END jev_dot_pipe
END LIBRARY

